VERSION 5.7 ;
  NOWIREEXTENSIONATPIN ON ;
  DIVIDERCHAR "/" ;
  BUSBITCHARS "[]" ;
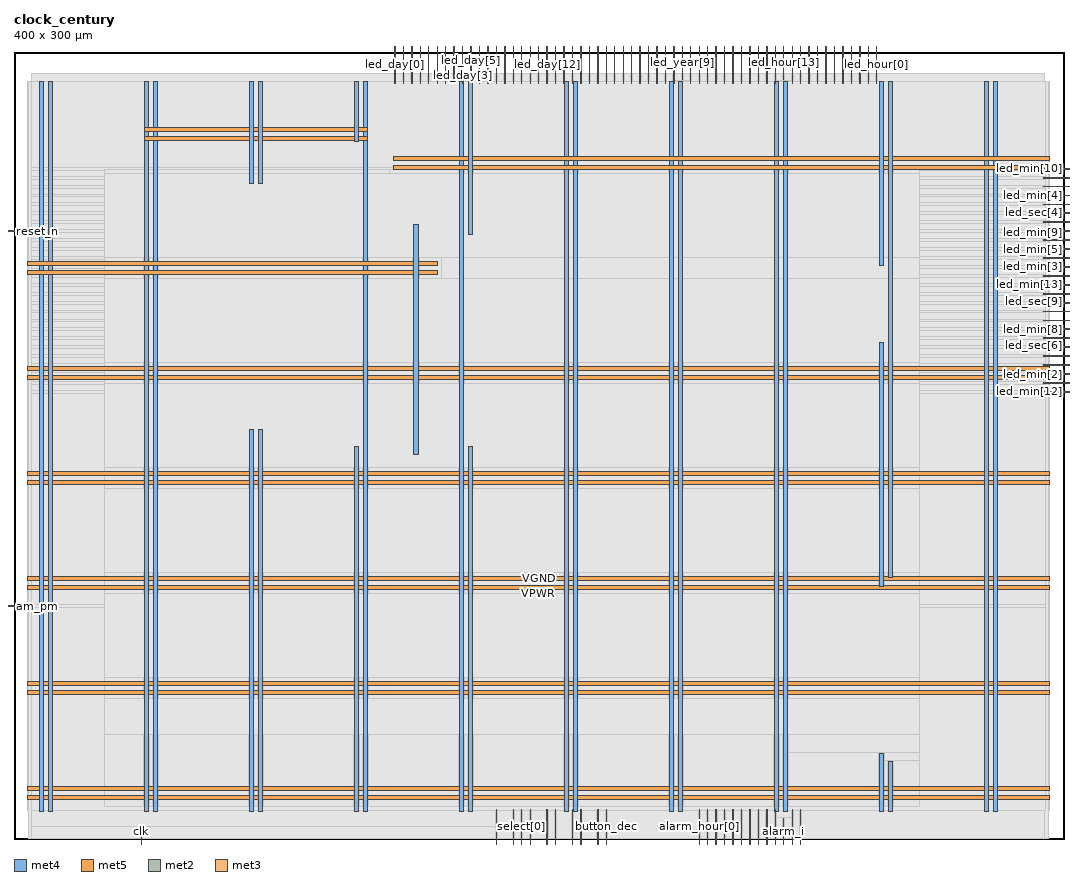
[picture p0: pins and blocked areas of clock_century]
MACRO clock_century
  CLASS BLOCK ;
  FOREIGN clock_century ;
  ORIGIN 0.000 0.000 ;
  SIZE 400.000 BY 300.000 ;
  PIN VGND
    DIRECTION INOUT ;
    USE GROUND ;
    PORT
      LAYER met4 ;
        RECT 13.020 10.640 14.620 288.560 ;
    END
    PORT
      LAYER met4 ;
        RECT 53.020 10.640 54.620 288.560 ;
    END
    PORT
      LAYER met4 ;
        RECT 93.020 10.640 94.620 155.995 ;
    END
    PORT
      LAYER met4 ;
        RECT 93.020 249.685 94.620 288.560 ;
    END
    PORT
      LAYER met4 ;
        RECT 133.020 10.640 134.620 288.560 ;
    END
    PORT
      LAYER met4 ;
        RECT 173.020 10.640 174.620 149.380 ;
    END
    PORT
      LAYER met4 ;
        RECT 173.020 230.460 174.620 288.560 ;
    END
    PORT
      LAYER met4 ;
        RECT 213.020 10.640 214.620 288.560 ;
    END
    PORT
      LAYER met4 ;
        RECT 253.020 10.640 254.620 288.560 ;
    END
    PORT
      LAYER met4 ;
        RECT 293.020 10.640 294.620 288.560 ;
    END
    PORT
      LAYER met4 ;
        RECT 333.020 10.640 334.620 29.380 ;
    END
    PORT
      LAYER met4 ;
        RECT 333.020 99.580 334.620 288.560 ;
    END
    PORT
      LAYER met4 ;
        RECT 373.020 10.640 374.620 288.560 ;
    END
    PORT
      LAYER met5 ;
        RECT 5.280 18.380 394.460 19.980 ;
    END
    PORT
      LAYER met5 ;
        RECT 5.280 58.380 394.460 59.980 ;
    END
    PORT
      LAYER met5 ;
        RECT 5.280 98.380 394.460 99.980 ;
    END
    PORT
      LAYER met5 ;
        RECT 5.280 138.380 394.460 139.980 ;
    END
    PORT
      LAYER met5 ;
        RECT 5.280 178.380 394.460 179.980 ;
    END
    PORT
      LAYER met5 ;
        RECT 5.280 218.380 161.420 219.980 ;
    END
    PORT
      LAYER met5 ;
        RECT 144.600 258.380 394.460 259.980 ;
    END
    PORT
      LAYER met4 ;
        RECT 152.380 146.640 153.980 234.160 ;
    END
    PORT
      LAYER met5 ;
        RECT 49.720 269.500 134.620 271.100 ;
    END
  END VGND
  PIN VPWR
    DIRECTION INOUT ;
    USE POWER ;
    PORT
      LAYER met4 ;
        RECT 9.720 10.640 11.320 288.560 ;
    END
    PORT
      LAYER met4 ;
        RECT 49.720 10.640 51.320 288.560 ;
    END
    PORT
      LAYER met4 ;
        RECT 89.720 10.640 91.320 155.995 ;
    END
    PORT
      LAYER met4 ;
        RECT 89.720 249.685 91.320 288.560 ;
    END
    PORT
      LAYER met4 ;
        RECT 129.720 10.640 131.320 149.380 ;
    END
    PORT
      LAYER met4 ;
        RECT 129.720 265.820 131.320 288.560 ;
    END
    PORT
      LAYER met4 ;
        RECT 169.720 10.640 171.320 288.560 ;
    END
    PORT
      LAYER met4 ;
        RECT 209.720 10.640 211.320 288.560 ;
    END
    PORT
      LAYER met4 ;
        RECT 249.720 10.640 251.320 288.560 ;
    END
    PORT
      LAYER met4 ;
        RECT 289.720 10.640 291.320 288.560 ;
    END
    PORT
      LAYER met4 ;
        RECT 329.720 10.640 331.320 32.680 ;
    END
    PORT
      LAYER met4 ;
        RECT 329.720 96.280 331.320 189.315 ;
    END
    PORT
      LAYER met4 ;
        RECT 329.720 218.405 331.320 288.560 ;
    END
    PORT
      LAYER met4 ;
        RECT 369.720 10.640 371.320 288.560 ;
    END
    PORT
      LAYER met5 ;
        RECT 5.280 15.080 394.460 16.680 ;
    END
    PORT
      LAYER met5 ;
        RECT 5.280 55.080 394.460 56.680 ;
    END
    PORT
      LAYER met5 ;
        RECT 5.280 95.080 394.460 96.680 ;
    END
    PORT
      LAYER met5 ;
        RECT 5.280 135.080 394.460 136.680 ;
    END
    PORT
      LAYER met5 ;
        RECT 5.280 175.080 394.460 176.680 ;
    END
    PORT
      LAYER met5 ;
        RECT 5.280 215.080 161.420 216.680 ;
    END
    PORT
      LAYER met5 ;
        RECT 144.600 255.080 394.460 256.680 ;
    END
    PORT
      LAYER met5 ;
        RECT 49.720 266.100 134.620 267.700 ;
    END
  END VPWR
  PIN alarm_hour[0]
    DIRECTION INPUT ;
    USE SIGNAL ;
    ANTENNAGATEAREA 0.631200 ;
    ANTENNADIFFAREA 0.434700 ;
    PORT
      LAYER met2 ;
        RECT 260.980 -2.000 261.120 11.260 ;
    END
  END alarm_hour[0]
  PIN alarm_hour[1]
    DIRECTION INPUT ;
    USE SIGNAL ;
    ANTENNAGATEAREA 0.631200 ;
    ANTENNADIFFAREA 0.434700 ;
    PORT
      LAYER met2 ;
        RECT 280.300 -2.000 280.440 11.260 ;
    END
  END alarm_hour[1]
  PIN alarm_hour[2]
    DIRECTION INPUT ;
    USE SIGNAL ;
    ANTENNAGATEAREA 0.631200 ;
    ANTENNADIFFAREA 0.434700 ;
    PORT
      LAYER met2 ;
        RECT 283.520 -2.000 283.660 11.260 ;
    END
  END alarm_hour[2]
  PIN alarm_hour[3]
    DIRECTION INPUT ;
    USE SIGNAL ;
    ANTENNAGATEAREA 0.631200 ;
    ANTENNADIFFAREA 0.434700 ;
    PORT
      LAYER met2 ;
        RECT 277.080 -2.000 277.220 11.260 ;
    END
  END alarm_hour[3]
  PIN alarm_hour[4]
    DIRECTION INPUT ;
    USE SIGNAL ;
    ANTENNAGATEAREA 0.631200 ;
    ANTENNADIFFAREA 0.434700 ;
    PORT
      LAYER met2 ;
        RECT 273.860 -2.000 274.000 11.260 ;
    END
  END alarm_hour[4]
  PIN alarm_i
    DIRECTION INPUT ;
    USE SIGNAL ;
    ANTENNAGATEAREA 0.631200 ;
    ANTENNADIFFAREA 0.434700 ;
    PORT
      LAYER met2 ;
        RECT 293.180 -2.000 293.320 7.890 ;
    END
  END alarm_i
  PIN alarm_min[0]
    DIRECTION INPUT ;
    USE SIGNAL ;
    ANTENNAGATEAREA 0.631200 ;
    ANTENNADIFFAREA 0.434700 ;
    PORT
      LAYER met2 ;
        RECT 299.620 -2.000 299.760 11.260 ;
    END
  END alarm_min[0]
  PIN alarm_min[1]
    DIRECTION INPUT ;
    USE SIGNAL ;
    ANTENNAGATEAREA 0.631200 ;
    ANTENNADIFFAREA 0.434700 ;
    PORT
      LAYER met2 ;
        RECT 289.960 -2.000 290.100 11.260 ;
    END
  END alarm_min[1]
  PIN alarm_min[2]
    DIRECTION INPUT ;
    USE SIGNAL ;
    ANTENNAGATEAREA 0.631200 ;
    ANTENNADIFFAREA 0.434700 ;
    PORT
      LAYER met2 ;
        RECT 296.400 -2.000 296.540 11.260 ;
    END
  END alarm_min[2]
  PIN alarm_min[3]
    DIRECTION INPUT ;
    USE SIGNAL ;
    ANTENNAGATEAREA 0.631200 ;
    ANTENNADIFFAREA 0.434700 ;
    PORT
      LAYER met2 ;
        RECT 286.740 -2.000 286.880 11.260 ;
    END
  END alarm_min[3]
  PIN alarm_min[4]
    DIRECTION INPUT ;
    USE SIGNAL ;
    ANTENNAGATEAREA 0.631200 ;
    ANTENNADIFFAREA 0.434700 ;
    PORT
      LAYER met2 ;
        RECT 267.420 -2.000 267.560 11.260 ;
    END
  END alarm_min[4]
  PIN alarm_min[5]
    DIRECTION INPUT ;
    USE SIGNAL ;
    ANTENNAGATEAREA 0.631200 ;
    ANTENNADIFFAREA 0.434700 ;
    PORT
      LAYER met2 ;
        RECT 264.200 -2.000 264.340 11.260 ;
    END
  END alarm_min[5]
  PIN alarm_o
    DIRECTION OUTPUT ;
    USE SIGNAL ;
    ANTENNADIFFAREA 0.445500 ;
    PORT
      LAYER met2 ;
        RECT 270.640 -2.000 270.780 11.260 ;
    END
  END alarm_o
  PIN am_pm
    DIRECTION INPUT ;
    USE SIGNAL ;
    ANTENNAGATEAREA 0.631200 ;
    ANTENNADIFFAREA 0.434700 ;
    PORT
      LAYER met3 ;
        RECT -2.000 88.590 6.990 88.890 ;
    END
  END am_pm
  PIN button_dec
    DIRECTION INPUT ;
    USE SIGNAL ;
    ANTENNAGATEAREA 0.631200 ;
    ANTENNADIFFAREA 0.434700 ;
    PORT
      LAYER met2 ;
        RECT 225.560 -2.000 225.700 11.260 ;
    END
  END button_dec
  PIN button_inc
    DIRECTION INPUT ;
    USE SIGNAL ;
    ANTENNAGATEAREA 0.631200 ;
    ANTENNADIFFAREA 0.434700 ;
    PORT
      LAYER met2 ;
        RECT 222.340 -2.000 222.480 11.260 ;
    END
  END button_inc
  PIN clk
    DIRECTION INPUT ;
    USE SIGNAL ;
    ANTENNAGATEAREA 1.286700 ;
    ANTENNADIFFAREA 0.434700 ;
    PORT
      LAYER met2 ;
        RECT 48.460 -2.000 48.600 4.490 ;
    END
  END clk
  PIN led_day[0]
    DIRECTION OUTPUT ;
    USE SIGNAL ;
    ANTENNADIFFAREA 0.445500 ;
    PORT
      LAYER met2 ;
        RECT 145.060 287.940 145.200 302.000 ;
    END
  END led_day[0]
  PIN led_day[10]
    DIRECTION OUTPUT ;
    USE SIGNAL ;
    ANTENNADIFFAREA 0.445500 ;
    PORT
      LAYER met2 ;
        RECT 180.480 287.940 180.620 302.000 ;
    END
  END led_day[10]
  PIN led_day[11]
    DIRECTION OUTPUT ;
    USE SIGNAL ;
    ANTENNADIFFAREA 0.445500 ;
    PORT
      LAYER met2 ;
        RECT 157.940 287.940 158.080 302.000 ;
    END
  END led_day[11]
  PIN led_day[12]
    DIRECTION OUTPUT ;
    USE SIGNAL ;
    ANTENNADIFFAREA 0.445500 ;
    PORT
      LAYER met2 ;
        RECT 203.020 287.940 203.160 302.000 ;
    END
  END led_day[12]
  PIN led_day[13]
    DIRECTION OUTPUT ;
    USE SIGNAL ;
    ANTENNADIFFAREA 0.445500 ;
    PORT
      LAYER met2 ;
        RECT 164.380 287.940 164.520 302.000 ;
    END
  END led_day[13]
  PIN led_day[1]
    DIRECTION OUTPUT ;
    USE SIGNAL ;
    ANTENNADIFFAREA 0.445500 ;
    PORT
      LAYER met2 ;
        RECT 183.700 287.940 183.840 302.000 ;
    END
  END led_day[1]
  PIN led_day[2]
    DIRECTION OUTPUT ;
    USE SIGNAL ;
    ANTENNADIFFAREA 0.445500 ;
    PORT
      LAYER met2 ;
        RECT 154.720 287.940 154.860 302.000 ;
    END
  END led_day[2]
  PIN led_day[3]
    DIRECTION OUTPUT ;
    USE SIGNAL ;
    ANTENNADIFFAREA 0.445500 ;
    PORT
      LAYER met2 ;
        RECT 170.820 287.940 170.960 302.000 ;
    END
  END led_day[3]
  PIN led_day[4]
    DIRECTION OUTPUT ;
    USE SIGNAL ;
    ANTENNADIFFAREA 0.445500 ;
    PORT
      LAYER met2 ;
        RECT 186.920 287.940 187.060 302.000 ;
    END
  END led_day[4]
  PIN led_day[5]
    DIRECTION OUTPUT ;
    USE SIGNAL ;
    ANTENNADIFFAREA 0.445500 ;
    PORT
      LAYER met2 ;
        RECT 174.040 291.310 174.180 302.000 ;
    END
  END led_day[5]
  PIN led_day[6]
    DIRECTION OUTPUT ;
    USE SIGNAL ;
    ANTENNADIFFAREA 0.445500 ;
    PORT
      LAYER met2 ;
        RECT 193.360 287.940 193.500 302.000 ;
    END
  END led_day[6]
  PIN led_day[7]
    DIRECTION OUTPUT ;
    USE SIGNAL ;
    ANTENNADIFFAREA 0.445500 ;
    PORT
      LAYER met2 ;
        RECT 167.600 287.940 167.740 302.000 ;
    END
  END led_day[7]
  PIN led_day[8]
    DIRECTION OUTPUT ;
    USE SIGNAL ;
    ANTENNADIFFAREA 0.445500 ;
    PORT
      LAYER met2 ;
        RECT 177.260 287.940 177.400 302.000 ;
    END
  END led_day[8]
  PIN led_day[9]
    DIRECTION OUTPUT ;
    USE SIGNAL ;
    ANTENNADIFFAREA 0.445500 ;
    PORT
      LAYER met2 ;
        RECT 190.140 287.940 190.280 302.000 ;
    END
  END led_day[9]
  PIN led_hour[0]
    DIRECTION OUTPUT ;
    USE SIGNAL ;
    ANTENNADIFFAREA 0.445500 ;
    PORT
      LAYER met2 ;
        RECT 328.600 287.940 328.740 302.000 ;
    END
  END led_hour[0]
  PIN led_hour[10]
    DIRECTION OUTPUT ;
    USE SIGNAL ;
    ANTENNADIFFAREA 0.445500 ;
    PORT
      LAYER met2 ;
        RECT 309.280 287.940 309.420 302.000 ;
    END
  END led_hour[10]
  PIN led_hour[11]
    DIRECTION OUTPUT ;
    USE SIGNAL ;
    ANTENNADIFFAREA 0.445500 ;
    PORT
      LAYER met2 ;
        RECT 296.400 287.940 296.540 302.000 ;
    END
  END led_hour[11]
  PIN led_hour[12]
    DIRECTION OUTPUT ;
    USE SIGNAL ;
    ANTENNADIFFAREA 0.445500 ;
    PORT
      LAYER met2 ;
        RECT 283.520 287.940 283.660 302.000 ;
    END
  END led_hour[12]
  PIN led_hour[13]
    DIRECTION OUTPUT ;
    USE SIGNAL ;
    ANTENNADIFFAREA 0.445500 ;
    PORT
      LAYER met2 ;
        RECT 293.180 289.270 293.320 302.000 ;
    END
  END led_hour[13]
  PIN led_hour[1]
    DIRECTION OUTPUT ;
    USE SIGNAL ;
    ANTENNADIFFAREA 0.445500 ;
    PORT
      LAYER met2 ;
        RECT 264.200 287.940 264.340 302.000 ;
    END
  END led_hour[1]
  PIN led_hour[2]
    DIRECTION OUTPUT ;
    USE SIGNAL ;
    ANTENNADIFFAREA 0.445500 ;
    PORT
      LAYER met2 ;
        RECT 306.060 287.940 306.200 302.000 ;
    END
  END led_hour[2]
  PIN led_hour[3]
    DIRECTION OUTPUT ;
    USE SIGNAL ;
    ANTENNADIFFAREA 0.445500 ;
    PORT
      LAYER met2 ;
        RECT 267.420 287.940 267.560 302.000 ;
    END
  END led_hour[3]
  PIN led_hour[4]
    DIRECTION OUTPUT ;
    USE SIGNAL ;
    ANTENNADIFFAREA 0.445500 ;
    PORT
      LAYER met2 ;
        RECT 302.840 287.940 302.980 302.000 ;
    END
  END led_hour[4]
  PIN led_hour[5]
    DIRECTION OUTPUT ;
    USE SIGNAL ;
    ANTENNADIFFAREA 0.445500 ;
    PORT
      LAYER met2 ;
        RECT 270.640 287.940 270.780 302.000 ;
    END
  END led_hour[5]
  PIN led_hour[6]
    DIRECTION OUTPUT ;
    USE SIGNAL ;
    ANTENNADIFFAREA 0.445500 ;
    PORT
      LAYER met2 ;
        RECT 299.620 287.940 299.760 302.000 ;
    END
  END led_hour[6]
  PIN led_hour[7]
    DIRECTION OUTPUT ;
    USE SIGNAL ;
    ANTENNADIFFAREA 0.445500 ;
    PORT
      LAYER met2 ;
        RECT 273.860 287.940 274.000 302.000 ;
    END
  END led_hour[7]
  PIN led_hour[8]
    DIRECTION OUTPUT ;
    USE SIGNAL ;
    ANTENNADIFFAREA 0.445500 ;
    PORT
      LAYER met2 ;
        RECT 277.080 287.940 277.220 302.000 ;
    END
  END led_hour[8]
  PIN led_hour[9]
    DIRECTION OUTPUT ;
    USE SIGNAL ;
    ANTENNADIFFAREA 0.445500 ;
    PORT
      LAYER met2 ;
        RECT 280.300 287.940 280.440 302.000 ;
    END
  END led_hour[9]
  PIN led_min[0]
    DIRECTION OUTPUT ;
    USE SIGNAL ;
    ANTENNADIFFAREA 0.445500 ;
    PORT
      LAYER met2 ;
        RECT 286.740 287.940 286.880 302.000 ;
    END
  END led_min[0]
  PIN led_min[10]
    DIRECTION OUTPUT ;
    USE SIGNAL ;
    ANTENNADIFFAREA 0.445500 ;
    PORT
      LAYER met3 ;
        RECT 392.290 255.190 402.000 255.490 ;
    END
  END led_min[10]
  PIN led_min[11]
    DIRECTION OUTPUT ;
    USE SIGNAL ;
    ANTENNADIFFAREA 0.445500 ;
    PORT
      LAYER met3 ;
        RECT 392.290 238.190 402.000 238.490 ;
    END
  END led_min[11]
  PIN led_min[12]
    DIRECTION OUTPUT ;
    USE SIGNAL ;
    ANTENNADIFFAREA 0.445500 ;
    PORT
      LAYER met3 ;
        RECT 392.750 170.190 402.000 170.490 ;
    END
  END led_min[12]
  PIN led_min[13]
    DIRECTION OUTPUT ;
    USE SIGNAL ;
    ANTENNADIFFAREA 0.445500 ;
    PORT
      LAYER met3 ;
        RECT 392.290 210.990 402.000 211.290 ;
    END
  END led_min[13]
  PIN led_min[1]
    DIRECTION OUTPUT ;
    USE SIGNAL ;
    ANTENNADIFFAREA 0.445500 ;
    PORT
      LAYER met2 ;
        RECT 289.960 287.940 290.100 302.000 ;
    END
  END led_min[1]
  PIN led_min[2]
    DIRECTION OUTPUT ;
    USE SIGNAL ;
    ANTENNADIFFAREA 0.445500 ;
    PORT
      LAYER met3 ;
        RECT 392.290 176.990 402.000 177.290 ;
    END
  END led_min[2]
  PIN led_min[3]
    DIRECTION OUTPUT ;
    USE SIGNAL ;
    ANTENNADIFFAREA 0.445500 ;
    PORT
      LAYER met3 ;
        RECT 392.290 217.790 402.000 218.090 ;
    END
  END led_min[3]
  PIN led_min[4]
    DIRECTION OUTPUT ;
    USE SIGNAL ;
    ANTENNADIFFAREA 0.445500 ;
    PORT
      LAYER met3 ;
        RECT 392.290 244.990 402.000 245.290 ;
    END
  END led_min[4]
  PIN led_min[5]
    DIRECTION OUTPUT ;
    USE SIGNAL ;
    ANTENNADIFFAREA 0.445500 ;
    PORT
      LAYER met3 ;
        RECT 392.290 224.590 402.000 224.890 ;
    END
  END led_min[5]
  PIN led_min[6]
    DIRECTION OUTPUT ;
    USE SIGNAL ;
    ANTENNADIFFAREA 0.445500 ;
    PORT
      LAYER met3 ;
        RECT 392.290 197.390 402.000 197.690 ;
    END
  END led_min[6]
  PIN led_min[7]
    DIRECTION OUTPUT ;
    USE SIGNAL ;
    ANTENNADIFFAREA 0.445500 ;
    PORT
      LAYER met3 ;
        RECT 392.290 183.790 402.000 184.090 ;
    END
  END led_min[7]
  PIN led_min[8]
    DIRECTION OUTPUT ;
    USE SIGNAL ;
    ANTENNADIFFAREA 0.445500 ;
    PORT
      LAYER met3 ;
        RECT 392.290 193.990 402.000 194.290 ;
    END
  END led_min[8]
  PIN led_min[9]
    DIRECTION OUTPUT ;
    USE SIGNAL ;
    ANTENNADIFFAREA 0.445500 ;
    PORT
      LAYER met3 ;
        RECT 392.290 227.990 402.000 228.290 ;
    END
  END led_min[9]
  PIN led_month[0]
    DIRECTION OUTPUT ;
    USE SIGNAL ;
    ANTENNADIFFAREA 0.445500 ;
    PORT
      LAYER met2 ;
        RECT 206.240 287.940 206.380 302.000 ;
    END
  END led_month[0]
  PIN led_month[10]
    DIRECTION OUTPUT ;
    USE SIGNAL ;
    ANTENNADIFFAREA 0.445500 ;
    PORT
      LAYER met2 ;
        RECT 151.500 287.940 151.640 302.000 ;
    END
  END led_month[10]
  PIN led_month[11]
    DIRECTION OUTPUT ;
    USE SIGNAL ;
    ANTENNADIFFAREA 0.445500 ;
    PORT
      LAYER met2 ;
        RECT 228.780 287.940 228.920 302.000 ;
    END
  END led_month[11]
  PIN led_month[12]
    DIRECTION OUTPUT ;
    USE SIGNAL ;
    ANTENNADIFFAREA 0.445500 ;
    PORT
      LAYER met2 ;
        RECT 222.340 287.940 222.480 302.000 ;
    END
  END led_month[12]
  PIN led_month[13]
    DIRECTION OUTPUT ;
    USE SIGNAL ;
    ANTENNADIFFAREA 0.445500 ;
    PORT
      LAYER met2 ;
        RECT 232.000 287.940 232.140 302.000 ;
    END
  END led_month[13]
  PIN led_month[1]
    DIRECTION OUTPUT ;
    USE SIGNAL ;
    ANTENNADIFFAREA 0.445500 ;
    PORT
      LAYER met2 ;
        RECT 209.460 287.940 209.600 302.000 ;
    END
  END led_month[1]
  PIN led_month[2]
    DIRECTION OUTPUT ;
    USE SIGNAL ;
    ANTENNADIFFAREA 0.445500 ;
    PORT
      LAYER met2 ;
        RECT 212.680 287.940 212.820 302.000 ;
    END
  END led_month[2]
  PIN led_month[3]
    DIRECTION OUTPUT ;
    USE SIGNAL ;
    ANTENNADIFFAREA 0.445500 ;
    PORT
      LAYER met2 ;
        RECT 161.160 287.940 161.300 302.000 ;
    END
  END led_month[3]
  PIN led_month[4]
    DIRECTION OUTPUT ;
    USE SIGNAL ;
    ANTENNADIFFAREA 0.445500 ;
    PORT
      LAYER met2 ;
        RECT 199.800 287.940 199.940 302.000 ;
    END
  END led_month[4]
  PIN led_month[5]
    DIRECTION OUTPUT ;
    USE SIGNAL ;
    ANTENNADIFFAREA 0.445500 ;
    PORT
      LAYER met2 ;
        RECT 148.280 287.940 148.420 302.000 ;
    END
  END led_month[5]
  PIN led_month[6]
    DIRECTION OUTPUT ;
    USE SIGNAL ;
    ANTENNADIFFAREA 0.445500 ;
    PORT
      LAYER met2 ;
        RECT 215.900 287.940 216.040 302.000 ;
    END
  END led_month[6]
  PIN led_month[7]
    DIRECTION OUTPUT ;
    USE SIGNAL ;
    ANTENNADIFFAREA 0.445500 ;
    PORT
      LAYER met2 ;
        RECT 196.580 287.940 196.720 302.000 ;
    END
  END led_month[7]
  PIN led_month[8]
    DIRECTION OUTPUT ;
    USE SIGNAL ;
    ANTENNADIFFAREA 0.445500 ;
    PORT
      LAYER met2 ;
        RECT 219.120 287.940 219.260 302.000 ;
    END
  END led_month[8]
  PIN led_month[9]
    DIRECTION OUTPUT ;
    USE SIGNAL ;
    ANTENNADIFFAREA 0.445500 ;
    PORT
      LAYER met2 ;
        RECT 225.560 287.940 225.700 302.000 ;
    END
  END led_month[9]
  PIN led_sec[0]
    DIRECTION OUTPUT ;
    USE SIGNAL ;
    ANTENNADIFFAREA 0.445500 ;
    PORT
      LAYER met3 ;
        RECT 392.290 251.790 402.000 252.090 ;
    END
  END led_sec[0]
  PIN led_sec[10]
    DIRECTION OUTPUT ;
    USE SIGNAL ;
    ANTENNADIFFAREA 0.445500 ;
    PORT
      LAYER met3 ;
        RECT 392.290 231.390 402.000 231.690 ;
    END
  END led_sec[10]
  PIN led_sec[11]
    DIRECTION OUTPUT ;
    USE SIGNAL ;
    ANTENNADIFFAREA 0.445500 ;
    PORT
      LAYER met3 ;
        RECT 392.290 248.390 402.000 248.690 ;
    END
  END led_sec[11]
  PIN led_sec[12]
    DIRECTION OUTPUT ;
    USE SIGNAL ;
    ANTENNADIFFAREA 0.445500 ;
    PORT
      LAYER met3 ;
        RECT 392.290 234.790 402.000 235.090 ;
    END
  END led_sec[12]
  PIN led_sec[13]
    DIRECTION OUTPUT ;
    USE SIGNAL ;
    ANTENNADIFFAREA 0.445500 ;
    PORT
      LAYER met3 ;
        RECT 392.290 200.790 402.000 201.090 ;
    END
  END led_sec[13]
  PIN led_sec[1]
    DIRECTION OUTPUT ;
    USE SIGNAL ;
    ANTENNADIFFAREA 0.445500 ;
    PORT
      LAYER met3 ;
        RECT 392.290 173.590 402.000 173.890 ;
    END
  END led_sec[1]
  PIN led_sec[2]
    DIRECTION OUTPUT ;
    USE SIGNAL ;
    ANTENNADIFFAREA 0.445500 ;
    PORT
      LAYER met3 ;
        RECT 392.290 221.190 402.000 221.490 ;
    END
  END led_sec[2]
  PIN led_sec[3]
    DIRECTION OUTPUT ;
    USE SIGNAL ;
    ANTENNADIFFAREA 0.445500 ;
    PORT
      LAYER met3 ;
        RECT 392.290 187.190 402.000 187.490 ;
    END
  END led_sec[3]
  PIN led_sec[4]
    DIRECTION OUTPUT ;
    USE SIGNAL ;
    ANTENNADIFFAREA 0.445500 ;
    PORT
      LAYER met3 ;
        RECT 392.290 241.590 402.000 241.890 ;
    END
  END led_sec[4]
  PIN led_sec[5]
    DIRECTION OUTPUT ;
    USE SIGNAL ;
    ANTENNADIFFAREA 0.445500 ;
    PORT
      LAYER met3 ;
        RECT 392.290 214.390 402.000 214.690 ;
    END
  END led_sec[5]
  PIN led_sec[6]
    DIRECTION OUTPUT ;
    USE SIGNAL ;
    ANTENNADIFFAREA 0.445500 ;
    PORT
      LAYER met3 ;
        RECT 392.290 190.590 402.000 190.890 ;
    END
  END led_sec[6]
  PIN led_sec[7]
    DIRECTION OUTPUT ;
    USE SIGNAL ;
    ANTENNADIFFAREA 0.445500 ;
    PORT
      LAYER met3 ;
        RECT 392.290 180.390 402.000 180.690 ;
    END
  END led_sec[7]
  PIN led_sec[8]
    DIRECTION OUTPUT ;
    USE SIGNAL ;
    ANTENNADIFFAREA 0.445500 ;
    PORT
      LAYER met3 ;
        RECT 392.290 204.190 402.000 204.490 ;
    END
  END led_sec[8]
  PIN led_sec[9]
    DIRECTION OUTPUT ;
    USE SIGNAL ;
    ANTENNADIFFAREA 0.445500 ;
    PORT
      LAYER met3 ;
        RECT 392.290 207.590 402.000 207.890 ;
    END
  END led_sec[9]
  PIN led_year[0]
    DIRECTION OUTPUT ;
    USE SIGNAL ;
    ANTENNADIFFAREA 0.445500 ;
    PORT
      LAYER met2 ;
        RECT 235.220 287.940 235.360 302.000 ;
    END
  END led_year[0]
  PIN led_year[10]
    DIRECTION OUTPUT ;
    USE SIGNAL ;
    ANTENNADIFFAREA 0.445500 ;
    PORT
      LAYER met2 ;
        RECT 315.720 287.940 315.860 302.000 ;
    END
  END led_year[10]
  PIN led_year[11]
    DIRECTION OUTPUT ;
    USE SIGNAL ;
    ANTENNADIFFAREA 0.445500 ;
    PORT
      LAYER met2 ;
        RECT 312.500 287.940 312.640 302.000 ;
    END
  END led_year[11]
  PIN led_year[12]
    DIRECTION OUTPUT ;
    USE SIGNAL ;
    ANTENNADIFFAREA 0.445500 ;
    PORT
      LAYER met2 ;
        RECT 257.760 287.940 257.900 302.000 ;
    END
  END led_year[12]
  PIN led_year[13]
    DIRECTION OUTPUT ;
    USE SIGNAL ;
    ANTENNADIFFAREA 0.445500 ;
    PORT
      LAYER met2 ;
        RECT 260.980 287.940 261.120 302.000 ;
    END
  END led_year[13]
  PIN led_year[1]
    DIRECTION OUTPUT ;
    USE SIGNAL ;
    ANTENNADIFFAREA 0.445500 ;
    PORT
      LAYER met2 ;
        RECT 238.440 287.940 238.580 302.000 ;
    END
  END led_year[1]
  PIN led_year[2]
    DIRECTION OUTPUT ;
    USE SIGNAL ;
    ANTENNADIFFAREA 0.445500 ;
    PORT
      LAYER met2 ;
        RECT 325.380 287.940 325.520 302.000 ;
    END
  END led_year[2]
  PIN led_year[3]
    DIRECTION OUTPUT ;
    USE SIGNAL ;
    ANTENNADIFFAREA 0.445500 ;
    PORT
      LAYER met2 ;
        RECT 241.660 287.940 241.800 302.000 ;
    END
  END led_year[3]
  PIN led_year[4]
    DIRECTION OUTPUT ;
    USE SIGNAL ;
    ANTENNADIFFAREA 0.445500 ;
    PORT
      LAYER met2 ;
        RECT 322.160 287.940 322.300 302.000 ;
    END
  END led_year[4]
  PIN led_year[5]
    DIRECTION OUTPUT ;
    USE SIGNAL ;
    ANTENNADIFFAREA 0.445500 ;
    PORT
      LAYER met2 ;
        RECT 244.880 287.940 245.020 302.000 ;
    END
  END led_year[5]
  PIN led_year[6]
    DIRECTION OUTPUT ;
    USE SIGNAL ;
    ANTENNADIFFAREA 0.445500 ;
    PORT
      LAYER met2 ;
        RECT 318.940 287.940 319.080 302.000 ;
    END
  END led_year[6]
  PIN led_year[7]
    DIRECTION OUTPUT ;
    USE SIGNAL ;
    ANTENNADIFFAREA 0.445500 ;
    PORT
      LAYER met2 ;
        RECT 248.100 287.940 248.240 302.000 ;
    END
  END led_year[7]
  PIN led_year[8]
    DIRECTION OUTPUT ;
    USE SIGNAL ;
    ANTENNADIFFAREA 0.445500 ;
    PORT
      LAYER met2 ;
        RECT 251.320 287.940 251.460 302.000 ;
    END
  END led_year[8]
  PIN led_year[9]
    DIRECTION OUTPUT ;
    USE SIGNAL ;
    ANTENNADIFFAREA 0.445500 ;
    PORT
      LAYER met2 ;
        RECT 254.540 289.270 254.680 302.000 ;
    END
  END led_year[9]
  PIN mode[0]
    DIRECTION INPUT ;
    USE SIGNAL ;
    ANTENNAGATEAREA 0.631200 ;
    ANTENNADIFFAREA 0.434700 ;
    PORT
      LAYER met2 ;
        RECT 183.700 -2.000 183.840 11.260 ;
    END
  END mode[0]
  PIN mode[1]
    DIRECTION INPUT ;
    USE SIGNAL ;
    ANTENNAGATEAREA 0.631200 ;
    ANTENNADIFFAREA 0.434700 ;
    PORT
      LAYER met2 ;
        RECT 190.140 -2.000 190.280 11.260 ;
    END
  END mode[1]
  PIN reset_n
    DIRECTION INPUT ;
    USE SIGNAL ;
    ANTENNAGATEAREA 0.631200 ;
    ANTENNADIFFAREA 0.434700 ;
    PORT
      LAYER met3 ;
        RECT -2.000 231.390 6.530 231.690 ;
    END
  END reset_n
  PIN select[0]
    DIRECTION INPUT ;
    USE SIGNAL ;
    ANTENNAGATEAREA 0.631200 ;
    ANTENNADIFFAREA 0.434700 ;
    PORT
      LAYER met2 ;
        RECT 193.360 -2.000 193.500 11.260 ;
    END
  END select[0]
  PIN select[1]
    DIRECTION INPUT ;
    USE SIGNAL ;
    ANTENNAGATEAREA 0.631200 ;
    ANTENNADIFFAREA 0.434700 ;
    PORT
      LAYER met2 ;
        RECT 196.580 -2.000 196.720 11.260 ;
    END
  END select[1]
  PIN select[2]
    DIRECTION INPUT ;
    USE SIGNAL ;
    ANTENNAGATEAREA 0.631200 ;
    ANTENNADIFFAREA 0.434700 ;
    PORT
      LAYER met2 ;
        RECT 203.020 -2.000 203.160 11.260 ;
    END
  END select[2]
  PIN select[3]
    DIRECTION INPUT ;
    USE SIGNAL ;
    ANTENNAGATEAREA 0.631200 ;
    ANTENNADIFFAREA 0.434700 ;
    PORT
      LAYER met2 ;
        RECT 206.240 -2.000 206.380 11.260 ;
    END
  END select[3]
  PIN select[4]
    DIRECTION INPUT ;
    USE SIGNAL ;
    ANTENNAGATEAREA 0.631200 ;
    ANTENNADIFFAREA 0.434700 ;
    PORT
      LAYER met2 ;
        RECT 212.680 -2.000 212.820 11.260 ;
    END
  END select[4]
  PIN select[5]
    DIRECTION INPUT ;
    USE SIGNAL ;
    ANTENNAGATEAREA 0.631200 ;
    ANTENNADIFFAREA 0.434700 ;
    PORT
      LAYER met2 ;
        RECT 215.900 -2.000 216.040 11.260 ;
    END
  END select[5]
  OBS
      LAYER nwell ;
        RECT 5.330 10.795 394.410 288.405 ;
      LAYER li1 ;
        RECT 5.520 10.795 394.220 288.405 ;
      LAYER met1 ;
        RECT 5.520 0.380 394.220 288.560 ;
      LAYER met2 ;
        RECT 6.530 287.660 144.780 291.450 ;
        RECT 145.480 287.660 148.000 291.450 ;
        RECT 148.700 287.660 151.220 291.450 ;
        RECT 151.920 287.660 154.440 291.450 ;
        RECT 155.140 287.660 157.660 291.450 ;
        RECT 158.360 287.660 160.880 291.450 ;
        RECT 161.580 287.660 164.100 291.450 ;
        RECT 164.800 287.660 167.320 291.450 ;
        RECT 168.020 287.660 170.540 291.450 ;
        RECT 171.240 291.030 173.760 291.450 ;
        RECT 174.460 291.030 176.980 291.450 ;
        RECT 171.240 287.660 176.980 291.030 ;
        RECT 177.680 287.660 180.200 291.450 ;
        RECT 180.900 287.660 183.420 291.450 ;
        RECT 184.120 287.660 186.640 291.450 ;
        RECT 187.340 287.660 189.860 291.450 ;
        RECT 190.560 287.660 193.080 291.450 ;
        RECT 193.780 287.660 196.300 291.450 ;
        RECT 197.000 287.660 199.520 291.450 ;
        RECT 200.220 287.660 202.740 291.450 ;
        RECT 203.440 287.660 205.960 291.450 ;
        RECT 206.660 287.660 209.180 291.450 ;
        RECT 209.880 287.660 212.400 291.450 ;
        RECT 213.100 287.660 215.620 291.450 ;
        RECT 216.320 287.660 218.840 291.450 ;
        RECT 219.540 287.660 222.060 291.450 ;
        RECT 222.760 287.660 225.280 291.450 ;
        RECT 225.980 287.660 228.500 291.450 ;
        RECT 229.200 287.660 231.720 291.450 ;
        RECT 232.420 287.660 234.940 291.450 ;
        RECT 235.640 287.660 238.160 291.450 ;
        RECT 238.860 287.660 241.380 291.450 ;
        RECT 242.080 287.660 244.600 291.450 ;
        RECT 245.300 287.660 247.820 291.450 ;
        RECT 248.520 287.660 251.040 291.450 ;
        RECT 251.740 288.990 254.260 291.450 ;
        RECT 254.960 288.990 257.480 291.450 ;
        RECT 251.740 287.660 257.480 288.990 ;
        RECT 258.180 287.660 260.700 291.450 ;
        RECT 261.400 287.660 263.920 291.450 ;
        RECT 264.620 287.660 267.140 291.450 ;
        RECT 267.840 287.660 270.360 291.450 ;
        RECT 271.060 287.660 273.580 291.450 ;
        RECT 274.280 287.660 276.800 291.450 ;
        RECT 277.500 287.660 280.020 291.450 ;
        RECT 280.720 287.660 283.240 291.450 ;
        RECT 283.940 287.660 286.460 291.450 ;
        RECT 287.160 287.660 289.680 291.450 ;
        RECT 290.380 288.990 292.900 291.450 ;
        RECT 293.600 288.990 296.120 291.450 ;
        RECT 290.380 287.660 296.120 288.990 ;
        RECT 296.820 287.660 299.340 291.450 ;
        RECT 300.040 287.660 302.560 291.450 ;
        RECT 303.260 287.660 305.780 291.450 ;
        RECT 306.480 287.660 309.000 291.450 ;
        RECT 309.700 287.660 312.220 291.450 ;
        RECT 312.920 287.660 315.440 291.450 ;
        RECT 316.140 287.660 318.660 291.450 ;
        RECT 319.360 287.660 321.880 291.450 ;
        RECT 322.580 287.660 325.100 291.450 ;
        RECT 325.800 287.660 328.320 291.450 ;
        RECT 329.020 287.660 392.750 291.450 ;
        RECT 6.530 11.540 392.750 287.660 ;
        RECT 6.530 4.770 183.420 11.540 ;
        RECT 6.530 0.350 48.180 4.770 ;
        RECT 48.880 0.350 183.420 4.770 ;
        RECT 184.120 0.350 189.860 11.540 ;
        RECT 190.560 0.350 193.080 11.540 ;
        RECT 193.780 0.350 196.300 11.540 ;
        RECT 197.000 0.350 202.740 11.540 ;
        RECT 203.440 0.350 205.960 11.540 ;
        RECT 206.660 0.350 212.400 11.540 ;
        RECT 213.100 0.350 215.620 11.540 ;
        RECT 216.320 0.350 222.060 11.540 ;
        RECT 222.760 0.350 225.280 11.540 ;
        RECT 225.980 0.350 260.700 11.540 ;
        RECT 261.400 0.350 263.920 11.540 ;
        RECT 264.620 0.350 267.140 11.540 ;
        RECT 267.840 0.350 270.360 11.540 ;
        RECT 271.060 0.350 273.580 11.540 ;
        RECT 274.280 0.350 276.800 11.540 ;
        RECT 277.500 0.350 280.020 11.540 ;
        RECT 280.720 0.350 283.240 11.540 ;
        RECT 283.940 0.350 286.460 11.540 ;
        RECT 287.160 0.350 289.680 11.540 ;
        RECT 290.380 8.170 296.120 11.540 ;
        RECT 290.380 0.350 292.900 8.170 ;
        RECT 293.600 0.350 296.120 8.170 ;
        RECT 296.820 0.350 299.340 11.540 ;
        RECT 300.040 0.350 392.750 11.540 ;
      LAYER met3 ;
        RECT 6.505 255.890 392.775 288.485 ;
        RECT 6.505 254.790 391.890 255.890 ;
        RECT 6.505 252.490 392.775 254.790 ;
        RECT 6.505 251.390 391.890 252.490 ;
        RECT 6.505 249.090 392.775 251.390 ;
        RECT 6.505 247.990 391.890 249.090 ;
        RECT 6.505 245.690 392.775 247.990 ;
        RECT 6.505 244.590 391.890 245.690 ;
        RECT 6.505 242.290 392.775 244.590 ;
        RECT 6.505 241.190 391.890 242.290 ;
        RECT 6.505 238.890 392.775 241.190 ;
        RECT 6.505 237.790 391.890 238.890 ;
        RECT 6.505 235.490 392.775 237.790 ;
        RECT 6.505 234.390 391.890 235.490 ;
        RECT 6.505 232.090 392.775 234.390 ;
        RECT 6.930 230.990 391.890 232.090 ;
        RECT 6.505 228.690 392.775 230.990 ;
        RECT 6.505 227.590 391.890 228.690 ;
        RECT 6.505 225.290 392.775 227.590 ;
        RECT 6.505 224.190 391.890 225.290 ;
        RECT 6.505 221.890 392.775 224.190 ;
        RECT 6.505 220.790 391.890 221.890 ;
        RECT 6.505 218.490 392.775 220.790 ;
        RECT 6.505 217.390 391.890 218.490 ;
        RECT 6.505 215.090 392.775 217.390 ;
        RECT 6.505 213.990 391.890 215.090 ;
        RECT 6.505 211.690 392.775 213.990 ;
        RECT 6.505 210.590 391.890 211.690 ;
        RECT 6.505 208.290 392.775 210.590 ;
        RECT 6.505 207.190 391.890 208.290 ;
        RECT 6.505 204.890 392.775 207.190 ;
        RECT 6.505 203.790 391.890 204.890 ;
        RECT 6.505 201.490 392.775 203.790 ;
        RECT 6.505 200.390 391.890 201.490 ;
        RECT 6.505 198.090 392.775 200.390 ;
        RECT 6.505 196.990 391.890 198.090 ;
        RECT 6.505 194.690 392.775 196.990 ;
        RECT 6.505 193.590 391.890 194.690 ;
        RECT 6.505 191.290 392.775 193.590 ;
        RECT 6.505 190.190 391.890 191.290 ;
        RECT 6.505 187.890 392.775 190.190 ;
        RECT 6.505 186.790 391.890 187.890 ;
        RECT 6.505 184.490 392.775 186.790 ;
        RECT 6.505 183.390 391.890 184.490 ;
        RECT 6.505 181.090 392.775 183.390 ;
        RECT 6.505 179.990 391.890 181.090 ;
        RECT 6.505 177.690 392.775 179.990 ;
        RECT 6.505 176.590 391.890 177.690 ;
        RECT 6.505 174.290 392.775 176.590 ;
        RECT 6.505 173.190 391.890 174.290 ;
        RECT 6.505 170.890 392.775 173.190 ;
        RECT 6.505 169.790 392.350 170.890 ;
        RECT 6.505 89.290 392.775 169.790 ;
        RECT 7.390 88.190 392.775 89.290 ;
        RECT 6.505 10.715 392.775 88.190 ;
      LAYER met4 ;
        RECT 34.620 12.415 49.320 255.220 ;
        RECT 51.720 12.415 52.620 255.220 ;
        RECT 55.020 249.285 89.320 255.220 ;
        RECT 91.720 249.285 92.620 255.220 ;
        RECT 95.020 249.285 132.620 255.220 ;
        RECT 55.020 156.395 132.620 249.285 ;
        RECT 55.020 12.415 89.320 156.395 ;
        RECT 91.720 12.415 92.620 156.395 ;
        RECT 95.020 149.780 132.620 156.395 ;
        RECT 95.020 12.415 129.320 149.780 ;
        RECT 131.720 12.415 132.620 149.780 ;
        RECT 135.020 234.560 169.320 255.220 ;
        RECT 135.020 146.240 151.980 234.560 ;
        RECT 154.380 146.240 169.320 234.560 ;
        RECT 135.020 12.415 169.320 146.240 ;
        RECT 171.720 230.060 172.620 255.220 ;
        RECT 175.020 230.060 209.320 255.220 ;
        RECT 171.720 149.780 209.320 230.060 ;
        RECT 171.720 12.415 172.620 149.780 ;
        RECT 175.020 12.415 209.320 149.780 ;
        RECT 211.720 12.415 212.620 255.220 ;
        RECT 215.020 12.415 249.320 255.220 ;
        RECT 251.720 12.415 252.620 255.220 ;
        RECT 255.020 12.415 289.320 255.220 ;
        RECT 291.720 12.415 292.620 255.220 ;
        RECT 295.020 218.005 329.320 255.220 ;
        RECT 331.720 218.005 332.620 255.220 ;
        RECT 295.020 189.715 332.620 218.005 ;
        RECT 295.020 95.880 329.320 189.715 ;
        RECT 331.720 99.180 332.620 189.715 ;
        RECT 335.020 99.180 345.000 255.220 ;
        RECT 331.720 95.880 345.000 99.180 ;
        RECT 295.020 33.080 345.000 95.880 ;
        RECT 295.020 12.415 329.320 33.080 ;
        RECT 331.720 29.780 345.000 33.080 ;
        RECT 331.720 12.415 332.620 29.780 ;
        RECT 335.020 12.415 345.000 29.780 ;
      LAYER met5 ;
        RECT 34.620 253.480 143.000 255.220 ;
        RECT 34.620 221.580 345.000 253.480 ;
        RECT 163.020 213.480 345.000 221.580 ;
        RECT 34.620 181.580 345.000 213.480 ;
        RECT 34.620 141.580 345.000 173.480 ;
        RECT 34.620 101.580 345.000 133.480 ;
        RECT 34.620 61.580 345.000 93.480 ;
        RECT 34.620 39.980 345.000 53.480 ;
  END
END clock_century
END LIBRARY

